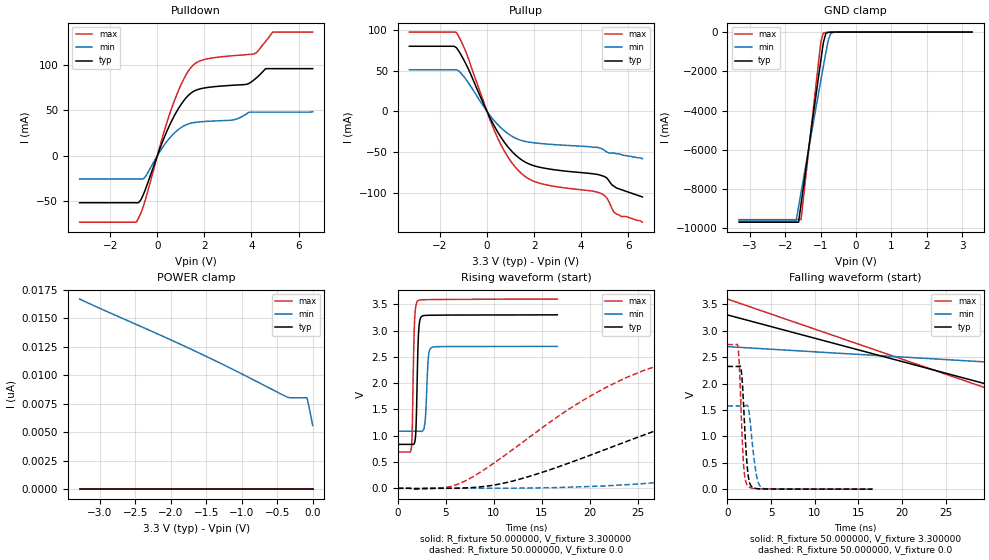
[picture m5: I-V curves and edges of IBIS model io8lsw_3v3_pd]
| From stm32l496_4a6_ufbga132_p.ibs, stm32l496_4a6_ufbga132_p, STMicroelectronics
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|   Model io8lsw_3v3_pd
[Model]  io8lsw_3v3_pd
Model_type I/O
Polarity   Non-Inverting
Enable   Active-Low
Vinl =   0.990000V
Vinh =   2.310000V
Vmeas =  1.650000V
Cref =   100.000000nF
Rref =   1.000000k
Vref =   3.300000V
C_comp   3.002600pF   2.845500pF   3.023700pF
[Temperature Range]   25.000000   0.125000k   -40.000000
[Pullup Reference]   3.300000V   2.700000V   3.600000V
[Pulldown Reference]   0.0V   0.0V   0.0V
[POWER Clamp Reference]   3.300000V   2.700000V   3.600000V
[GND Clamp Reference]   0.0V   0.0V   0.0V
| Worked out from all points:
|   slope of the pulldown table from 0 to 0.495 V, typ, clamps not added: 15.4 ohm
|   slope of the pullup table from 0 to 0.495 V, typ, clamps not added: 18.1 ohm
|   GND clamp passes 1 mA (typ) near -0.58 V on its own axis
|   rising waveform, R_fixture 50.000000, V_fixture 3.300000: 20-80 % time 195ps typ, 237ps min, 192ps max; typ from 0.835 V to 3.3 V
|   rising waveform, R_fixture 50.000000, V_fixture 0.0: 20-80 % time 24ns typ, 53.4ns min, 14.4ns max; typ from 0 V to 2.32 V
|   falling waveform, R_fixture 50.000000, V_fixture 3.300000: 20-80 % time 33.5ns typ, 61.1ns min, 30.7ns max; typ from 3.3 V to 0.835 V
|   falling waveform, R_fixture 50.000000, V_fixture 0.0: 20-80 % time 484ps typ, 657ps min, 409ps max; typ from 2.32 V to 0 V
[Pulldown]
|Voltage   I(typ)   I(min)   I(max)
-3.3V     -51.63mA   -25.53mA   -73.04mA
-900mV    -51.63mA   -25.53mA   -73.04mA
-500mV    -36.51mA   -22.79mA   -47.71mA
200mV     14.02mA    8.316mA    18.9mA
700mV     42.99mA    24.4mA     58.9mA
1.2V      63.06mA    33.8mA     88.14mA
1.6V      71.63mA    36.67mA    101.4mA
3.2V      77.51mA    39.29mA    110mA
4.1V      83.27mA    47.97mA    111.9mA
4.6V      95.8mA     47.97mA    125.7mA
4.9V      95.8mA     47.97mA    136mA
6.6V      95.8mA     48.43mA    136mA
[Pullup]
|Voltage   I(typ)   I(min)   I(max)
-3.3V     80.14mA    51.31mA    97.55mA
-1.3V     78.3mA     51.31mA    97.1mA
-900mV    58.48mA    39.59mA    73.21mA
100mV     -6.166mA   -3.962mA   -8.038mA
500mV     -27.53mA   -17.49mA   -35.6mA
1V        -47.29mA   -29.38mA   -60.81mA
1.5V      -60.05mA   -35.95mA   -77.15mA
2.4V      -69.45mA   -39.66mA   -89.34mA
4.8V      -78.1mA    -45mA      -100.2mA
5.1V      -82mA      -50mA      -106.7mA
5.5V      -94mA      -52mA      -126mA
6.6V      -105mA     -58mA      -136mA
[GND_clamp]
|Voltage   I(typ)   I(min)   I(max)
-3.3V     -9.687A    -9.633A    -9.557A
-1.69V    -9.687A    -9.633A    -9.557A
-1.62V    -9.687A    -8.894A    -9.557A
-1.55V    -8.764A    -8.167A    -9.557A
-1.13V    -3.236A    -3.867A    -2.713A
-990mV    -1.417A    -2.448A    -480.2mA
-920mV    -530mA     -1.746A    -39.97mA
-850mV    -62.37mA   -1.055A    -14.05mA
-780mV    -12.06mA   -390.4mA   -9.024mA
-710mV    -4.91mA    -69.1mA    -5.331mA
-640mV    -2.318mA   -14.6mA    -2.508mA
3.28V     87.11uA    88.99uA    71.58uA
[POWER_clamp]
|Voltage   I(typ)   I(min)   I(max)
-3.28V    0A         16.68nA    0A
-1.64V    0A         12.07nA    0A
-1.08V    0A         10.37nA    0A
-360mV    0A         8.078nA    0A
-320mV    0A         8.02nA     0A
-80mV     0A         8.02nA     0A
-40mV     0A         6.883nA    0A
0V        0A         5.582nA    0A
[Ramp]
| variable   typ   min   max
dV/dt_r  1.39404/23.92719n   0.94392/53.44857n   1.64256/14.36828n
dV/dt_f  1.47854/21.18525n   0.96612/44.48197n   1.74568/13.69982n
R_load = 50.000000
[Rising Waveform]
R_fixture= 50.000000
V_fixture= 3.300000
V_fixture_min= 2.700000
V_fixture_max= 3.600000
|time   V(typ)   V(min)   V(max)
0s        834.7mV    1.086V     689.8mV
1.435ns   834.1mV    1.086V     787.5mV
1.735ns   856.7mV    1.086V     3.1V
1.902ns   1.143V     1.086V     3.483V
2.102ns   2.664V     1.085V     3.567V
2.302ns   3.194V     1.084V     3.581V
2.803ns   3.287V     1.206V     3.587V
3.17ns    3.29V      2.444V     3.588V
3.504ns   3.292V     2.676V     3.589V
16.62ns   3.299V     2.699V     3.599V
[Rising Waveform]
R_fixture= 50.000000
V_fixture= 0.0
V_fixture_min= 0.0
V_fixture_max= 0.0
|time   V(typ)   V(min)   V(max)
0s        3.854nV    95.34nV    3.47nV
6.607ns   3.498mV    -136.4uV   103.2mV
13.21ns   199.4mV    4.589mV    903.6mV
19.82ns   613.5mV    32.98mV    1.729V
25.83ns   1.026V     92.5mV     2.256V
40.84ns   1.832V     359.8mV    2.636V
63.06ns   2.215V     821.3mV    2.719V
91.29ns   2.298V     1.251V     2.735V
117.1ns   2.315V     1.44V      2.737V
299.1ns   2.323V     1.574V     2.738V
[Falling Waveform]
R_fixture= 50.000000
V_fixture= 3.300000
V_fixture_min= 2.700000
V_fixture_max= 3.600000
|time   V(typ)   V(min)   V(max)
0s        3.299V     2.699V     3.599V
50.05ns   1.09V      2.208V     752.5mV
100.1ns   862.8mV    1.297V     694.3mV
150.2ns   839.5mV    1.145V     690.3mV
200.2ns   835.7mV    1.106V     689.8mV
300.3ns   834.7mV    1.089V     689.8mV
4.955us   834.7mV    1.086V     689.8mV
[Falling Waveform]
R_fixture= 50.000000
V_fixture= 0.0
V_fixture_min= 0.0
V_fixture_max= 0.0
|time   V(typ)   V(min)   V(max)
0s        2.323V     1.574V     2.738V
1.201ns   2.323V     1.574V     2.695V
1.368ns   2.329V     1.574V     2.339V
1.568ns   2.263V     1.574V     1.468V
1.869ns   1.524V     1.573V     421.9mV
2.135ns   715.4mV    1.581V     127.4mV
2.369ns   270.5mV    1.555V     57.52mV
3.237ns   13.79mV    350.3mV    9.325mV
3.837ns   5.352mV    34.81mV    5.535mV
16.62ns   3.854nV    95.34nV    3.47nV
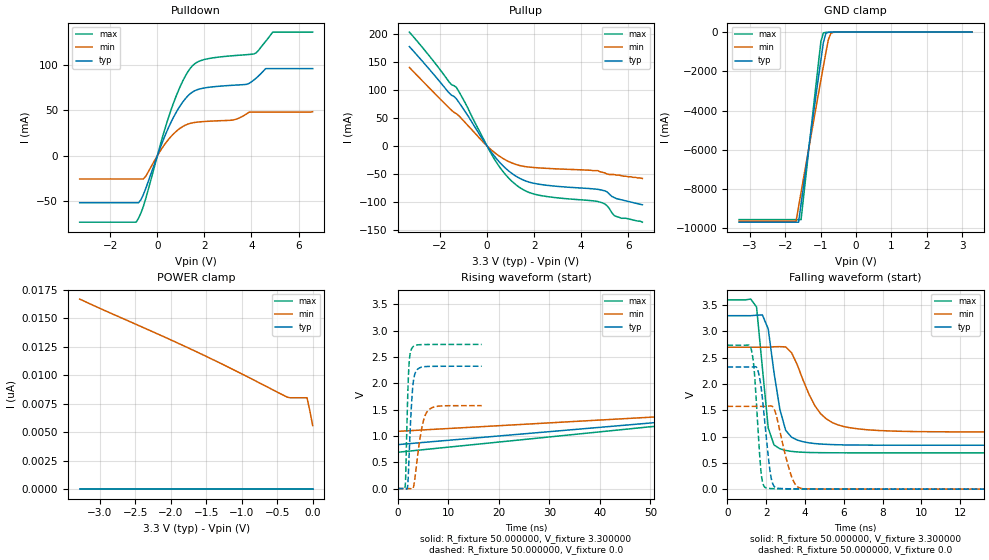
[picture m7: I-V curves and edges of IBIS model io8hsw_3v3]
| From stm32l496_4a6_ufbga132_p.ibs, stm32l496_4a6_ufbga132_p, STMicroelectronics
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|   Model io8hsw_3v3
[Model]  io8hsw_3v3
Model_type I/O
Polarity   Non-Inverting
Enable   Active-Low
Vinl =   0.990000V
Vinh =   2.310000V
Vmeas =  1.650000V
Cref =   100.000000nF
Rref =   1.000000k
Vref =   3.300000V
C_comp   2.968600pF   2.938100pF   3.196200pF
[Temperature Range]   25.000000   0.125000k   -40.000000
[Pullup Reference]   3.300000V   2.700000V   3.600000V
[Pulldown Reference]   0.0V   0.0V   0.0V
[POWER Clamp Reference]   3.300000V   2.700000V   3.600000V
[GND Clamp Reference]   0.0V   0.0V   0.0V
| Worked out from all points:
|   slope of the pulldown table from 0 to 0.495 V, typ, clamps not added: 15.4 ohm
|   slope of the pullup table from 0 to 0.495 V, typ, clamps not added: 18.1 ohm
|   GND clamp passes 1 mA (typ) near -0.58 V on its own axis
|   rising waveform, R_fixture 50.000000, V_fixture 3.300000: 20-80 % time 180ns typ, 180ns min, 180ns max; typ from 0.835 V to 3.3 V
|   rising waveform, R_fixture 50.000000, V_fixture 0.0: 20-80 % time 728ps typ, 1.47ns min, 490ps max; typ from 0 V to 2.33 V
|   falling waveform, R_fixture 50.000000, V_fixture 3.300000: 20-80 % time 656ps typ, 1.29ns min, 456ps max; typ from 3.3 V to 0.835 V
|   falling waveform, R_fixture 50.000000, V_fixture 0.0: 20-80 % time 393ps typ, 627ps min, 287ps max; typ from 2.33 V to 0 V
[Pulldown]
|Voltage   I(typ)   I(min)   I(max)
-3.3V     -51.62mA   -25.53mA   -73.04mA
-900mV    -51.62mA   -25.53mA   -73.04mA
-500mV    -36.51mA   -22.79mA   -47.71mA
200mV     14.03mA    8.316mA    18.9mA
700mV     42.99mA    24.4mA     58.9mA
1.2V      63.06mA    33.8mA     88.14mA
1.6V      71.64mA    36.67mA    101.4mA
3.2V      77.51mA    39.29mA    110mA
4.1V      83.27mA    47.97mA    111.9mA
4.6V      95.8mA     47.97mA    125.7mA
4.9V      95.8mA     47.97mA    136mA
6.6V      95.8mA     48.43mA    136mA
[Pullup]
|Voltage   I(typ)   I(min)   I(max)
-3.3V     177.2mA    140mA      203.1mA
-1.6V     93.96mA    67.34mA    113.4mA
-1.3V     83.97mA    57.45mA    104.3mA
300mV     -17.49mA   -11.19mA   -22.71mA
700mV     -36.32mA   -22.9mA    -46.84mA
1.2V      -53.2mA    -32.62mA   -68.33mA
1.7V      -63.36mA   -37.26mA   -81.47mA
2.2V      -68.23mA   -39.11mA   -87.81mA
4.8V      -78.1mA    -46mA      -100.2mA
5.1V      -82mA      -50mA      -106.7mA
5.5V      -94mA      -52mA      -126mA
6.6V      -105mA     -58mA      -136mA
[GND_clamp]
|Voltage   I(typ)   I(min)   I(max)
-3.3V     -9.687A    -9.633A    -9.557A
-1.69V    -9.687A    -9.633A    -9.557A
-1.62V    -9.687A    -8.894A    -9.557A
-1.55V    -8.764A    -8.167A    -9.557A
-1.13V    -3.236A    -3.867A    -2.713A
-990mV    -1.416A    -2.448A    -480.1mA
-920mV    -530mA     -1.746A    -39.96mA
-850mV    -62.36mA   -1.055A    -14.04mA
-780mV    -12.04mA   -390.4mA   -9.013mA
-710mV    -4.897mA   -69.08mA   -5.32mA
-640mV    -2.305mA   -14.59mA   -2.498mA
3.28V     0A         0A         0A
[POWER_clamp]
|Voltage   I(typ)   I(min)   I(max)
-3.28V    0A         16.68nA    0A
-1.64V    0A         12.07nA    0A
-1.08V    0A         10.37nA    0A
-360mV    0A         8.078nA    0A
-320mV    0A         8.02nA     0A
-80mV     0A         8.02nA     0A
-40mV     0A         6.883nA    0A
0V        0A         5.582nA    0A
[Ramp]
| variable   typ   min   max
dV/dt_r  1.39458/0.72755n   0.94494/1.46455n   1.64298/0.48961n
dV/dt_f  1.47876/0.60100n   0.96720/1.27403n   1.74587/0.40000n
R_load = 50.000000
[Rising Waveform]
R_fixture= 50.000000
V_fixture= 3.300000
V_fixture_min= 2.700000
V_fixture_max= 3.600000
|time   V(typ)   V(min)   V(max)
0s        835mV      1.087V     689.9mV
300.3ns   3.3V       2.7V       3.6V
600.6ns   3.3V       2.7V       3.6V
29.73us   3.3V       2.7V       3.6V
[Rising Waveform]
R_fixture= 50.000000
V_fixture= 0.0
V_fixture_min= 0.0
V_fixture_max= 0.0
|time   V(typ)   V(min)   V(max)
0s        3.976nV    71.73nV    3.582nV
1.468ns   291.4uV    322nV      40.79mV
1.568ns   -1.108mV   441.7nV    205.9mV
1.935ns   30.59mV    27.82uV    1.625V
2.169ns   430.8mV    114.6uV    2.244V
2.769ns   1.666V     -9.658mV   2.661V
3.504ns   2.206V     279.9mV    2.721V
4.738ns   2.308V     1.138V     2.735V
6.006ns   2.32V      1.483V     2.737V
16.62ns   2.325V     1.575V     2.739V
[Falling Waveform]
R_fixture= 50.000000
V_fixture= 3.300000
V_fixture_min= 2.700000
V_fixture_max= 3.600000
|time   V(typ)   V(min)   V(max)
0s        3.3V       2.7V       3.6V
1.502ns   3.309V     2.7V       3.465V
1.802ns   3.314V     2.7V       2.305V
2.102ns   3.05V      2.7V       1.163V
2.402ns   2.214V     2.709V     841.1mV
3.003ns   1.119V     2.706V     736.4mV
3.904ns   901.5mV    2.07V      702mV
5.405ns   847.6mV    1.267V     692.3mV
9.61ns    835.9mV    1.096V     690.6mV
149.5ns   835mV      1.087V     689.9mV
[Falling Waveform]
R_fixture= 50.000000
V_fixture= 0.0
V_fixture_min= 0.0
V_fixture_max= 0.0
|time   V(typ)   V(min)   V(max)
0s        2.325V     1.575V     2.739V
1.235ns   2.325V     1.575V     2.649V
1.401ns   2.33V      1.575V     2.16V
1.735ns   1.938V     1.575V     313.9mV
1.969ns   1.114V     1.575V     27.26mV
2.202ns   329.5mV    1.583V     12.44mV
2.369ns   76.7mV     1.551V     9.221mV
3.27ns    6.624mV    279.5mV    3.372mV
3.77ns    4.291mV    18.56mV    2.157mV
16.62ns   3.976nV    71.73nV    3.582nV
